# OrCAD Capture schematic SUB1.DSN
size A4; note: P5000197

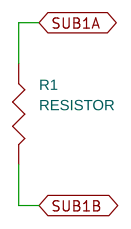
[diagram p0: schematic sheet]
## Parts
R1  RESISTOR  [0123]

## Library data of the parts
R1 = RESISTOR

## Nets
SUB1A: R1.1
SUB1B: R1.2
